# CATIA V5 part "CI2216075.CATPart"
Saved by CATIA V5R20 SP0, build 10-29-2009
Part number: CI2216075
Bounding box of the stored display mesh (mm): x -15 to 15, y -10.788 to 99, z -21.241 to 16.291
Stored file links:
  C:\Users\Raffaele\Desktop\3D X SITO CF\BOLEX\19-INCLINED ASSEMBLY REF_CI\CI2216075.CATPart

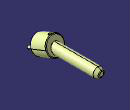
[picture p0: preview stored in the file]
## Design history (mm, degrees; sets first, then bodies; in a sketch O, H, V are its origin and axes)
Set1
  DatumSurface1 to DatumSurface16 "MANIFOLD_SOLID_BREP #381"
  DatumSurface17 to DatumSurface39 "MANIFOLD_SOLID_BREP #1139"
Body1 (main body)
